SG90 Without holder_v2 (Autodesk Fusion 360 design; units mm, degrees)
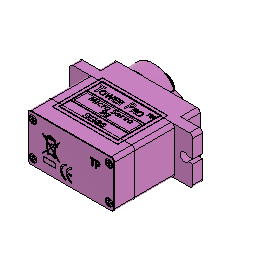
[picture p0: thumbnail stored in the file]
part number: SG90 - Micro Servo 9g - Tower Pro.1
base_feature "Base Feature"
component_insert "Component Insert"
